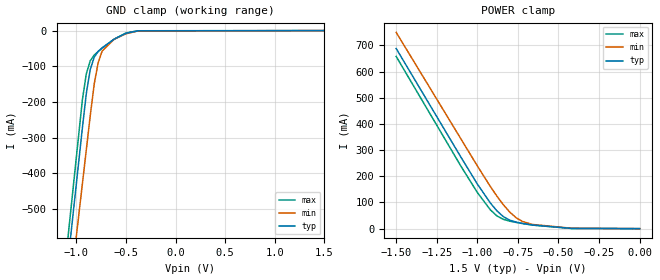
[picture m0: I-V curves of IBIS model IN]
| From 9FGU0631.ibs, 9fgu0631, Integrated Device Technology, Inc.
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|   Model IN
[Model]  IN
Model_type Input
Polarity   Non-Inverting
Enable   Active-High
Vinl =   0.4000V
Vinh =   0.9000V
C_comp   1.1000pF   1.0000pF   1.2000pF
[Temperature Range]   25.0000   75.0000   0.0
[Voltage Range]   1.5000V   1.4200V   1.5800V
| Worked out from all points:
|   GND clamp passes 1 mA (typ) near -0.39 V on its own axis
|   POWER clamp passes 1 mA (typ) near -0.42 V on its own axis
[GND_clamp]
|Voltage   I(typ)   I(min)   I(max)
-1.5V     -1.718A    -1.784A    -1.686A
-940mV    -275mA     -431.4mA   -195.6mA
-900mV    -177.1mA   -334.9mA   -121.7mA
-860mV    -109.2mA   -238.4mA   -84.65mA
-820mV    -74.51mA   -149.8mA   -68.78mA
-780mV    -58.47mA   -89.84mA   -58.68mA
-740mV    -48.23mA   -57.49mA   -49.43mA
-620mV    -24.29mA   -24.54mA   -24.23mA
-500mV    -7.526mA   -8.793mA   -6.78mA
-380mV    -746.2uA   -1.279mA   -529.5uA
1.5V      1.623nA    1.734uA    1.956uA
[POWER_clamp]
|Voltage   I(typ)   I(min)   I(max)
-1.5V     688.2mA    749.7mA    657.9mA
-1.1V     272mA      341.7mA    237.6mA
-1V       170.6mA    239.7mA    138.3mA
-920mV    98.29mA    161.3mA    72mA
-880mV    68.47mA    124.9mA    49.02mA
-840mV    46.04mA    91.71mA    35.66mA
-800mV    32.34mA    63.13mA    28.65mA
-760mV    24.79mA    41.15mA    23.72mA
-720mV    19.83mA    26.87mA    19.38mA
-660mV    14.01mA    16.07mA    13.56mA
-420mV    1.009mA    1.611mA    750uA
0V        1.623nA    20.57nA    406.1pA
